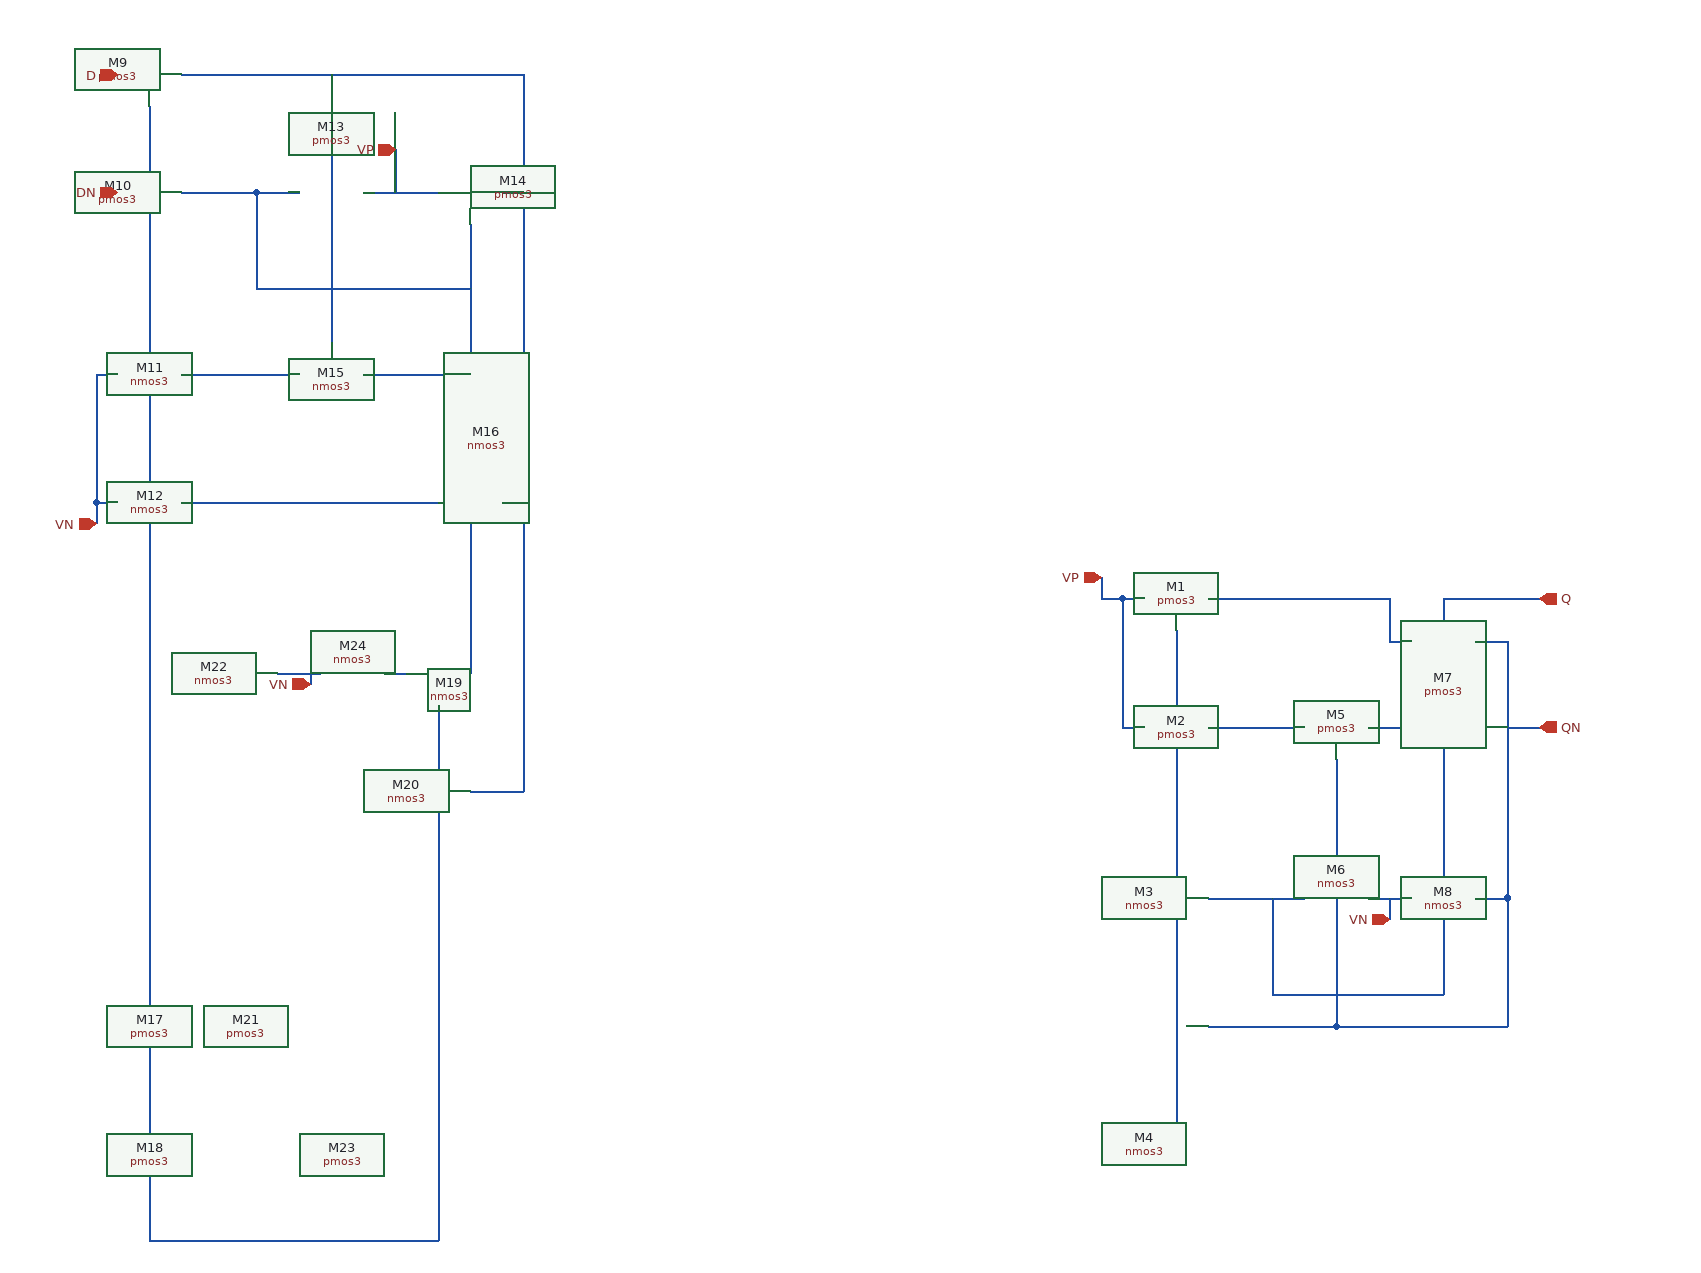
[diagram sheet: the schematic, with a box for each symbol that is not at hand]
v {xschem version=2.9.9 file_version=1.2 }
G {}
K {}
V {}
S {}
E {}
N 1230 -280 1320 -280 { lab=#net1}
N 1230 -120 1320 -120 { lab=Q}
N 1230 0 1350 0 { lab=QN}
N 1350 -250 1350 0 { lab=QN}
N 1380 -280 1450 -280 { lab=Q}
N 1450 -280 1450 -90 { lab=Q}
N 1380 -120 1420 -120 { lab=VN}
N 1480 -120 1510 -120 { lab=QN}
N 1150 -280 1170 -280 { lab=VP}
N 1150 -400 1150 -280 { lab=VP}
N 1150 -400 1170 -400 { lab=VP}
N 1350 0 1510 0 { lab=QN}
N 1510 -120 1510 0 { lab=QN}
N 1290 -120 1290 -60 { lab=Q}
N 1290 -30 1450 -30 { lab=Q}
N 1450 -90 1450 -60 { lab=Q}
N 270 -890 500 -890 { lab=#net2}
N 270 -780 340 -780 { lab=#net3}
N 270 -610 340 -610 { lab=#net4}
N 240 -860 240 -460 { lab=#net5}
N 240 -460 240 -400 { lab=#net5}
N 410 -890 410 -640 { lab=#net2}
N 440 -610 540 -610 { lab=#net3}
N 270 -490 470 -490 { lab=#net6}
N 190 -610 210 -610 { lab=VN}
N 190 -610 190 -490 { lab=VN}
N 190 -490 210 -490 { lab=VN}
N 340 -780 340 -690 { lab=#net3}
N 340 -690 540 -690 { lab=#net3}
N 540 -750 540 -520 { lab=#net3}
N 570 -490 590 -490 { lab=#net2}
N 590 -890 590 -490 { lab=#net2}
N 540 -890 590 -890 { lab=#net2}
N 570 -780 590 -780 { lab=#net2}
N 440 -780 510 -780 { lab=VP}
N 470 -820 470 -780 { lab=VP}
N 1200 -370 1200 90 { lab=#net7}
N 190 -490 190 -470 { lab=VN}
N 1130 -420 1130 -400 { lab=VP}
N 1130 -400 1150 -400 { lab=VP}
N 1290 -60 1290 -30 { lab=Q}
N 1450 -60 1450 -30 { lab=Q}
N 1400 -120 1400 -100 { lab=VN}
N 1510 -280 1540 -280 { lab=QN}
N 1480 -360 1510 -360 { lab=QN}
N 1400 -360 1420 -360 { lab=#net8}
N 1400 -400 1400 -360 { lab=#net8}
N 1230 -400 1400 -400 { lab=#net8}
N 1510 -360 1510 -120 { lab=QN}
N 1450 -400 1450 -280 { lab=Q}
N 1450 -400 1540 -400 { lab=Q}
N 540 -520 540 -330 { lab=#net3}
N 240 30 240 200 { lab=#net5}
N 590 -490 590 -220 { lab=#net2}
N 540 -220 590 -220 { lab=#net2}
N 380 -330 400 -330 { lab=VN}
N 390 -330 390 -320 { lab=VN}
N 240 -400 240 30 { lab=#net5}
N 240 200 470 200 { lab=#net5}
N 510 -300 510 200 { lab=#net9}
N 460 -330 480 -330 { lab=#net10}
N 500 -890 540 -890 { lab=#net2}
N 340 -780 380 -780 { lab=#net3}
N 340 -610 380 -610 { lab=#net4}
N 470 -490 510 -490 {}
N 360 -330 380 -330 {}
N 470 200 510 200 {}
C {madvlsi/pmos3.sym} 1200 -400 3 0 {name=M1
L=0.15
W=1
body=VDD
nf=1
mult=1
ad="'int((nf+1)/2) * W/nf * 0.29'" 
pd="'2*int((nf+1)/2) * (W/nf + 0.29)'"
as="'int((nf+2)/2) * W/nf * 0.29'" 
ps="'2*int((nf+2)/2) * (W/nf + 0.29)'"
nrd="'0.29 / W'" nrs="'0.29 / W'"
sa=0 sb=0 sd=0
model=pfet_01v8
spiceprefix=X
}
C {madvlsi/pmos3.sym} 1200 -280 3 0 {name=M2
L=0.15
W=1
body=VDD
nf=1
mult=1
ad="'int((nf+1)/2) * W/nf * 0.29'" 
pd="'2*int((nf+1)/2) * (W/nf + 0.29)'"
as="'int((nf+2)/2) * W/nf * 0.29'" 
ps="'2*int((nf+2)/2) * (W/nf + 0.29)'"
nrd="'0.29 / W'" nrs="'0.29 / W'"
sa=0 sb=0 sd=0
model=pfet_01v8
spiceprefix=X
}
C {madvlsi/nmos3.sym} 1200 -120 3 0 {name=M3
L=0.15
W=1
body=GND
nf=1
mult=1
ad="'int((nf+1)/2) * W/nf * 0.29'" 
pd="'2*int((nf+1)/2) * (W/nf + 0.29)'"
as="'int((nf+2)/2) * W/nf * 0.29'" 
ps="'2*int((nf+2)/2) * (W/nf + 0.29)'"
nrd="'0.29 / W'" nrs="'0.29 / W'"
sa=0 sb=0 sd=0
model=nfet_01v8
spiceprefix=X
}
C {madvlsi/nmos3.sym} 1200 0 3 0 {name=M4
L=0.15
W=1
body=GND
nf=1
mult=1
ad="'int((nf+1)/2) * W/nf * 0.29'" 
pd="'2*int((nf+1)/2) * (W/nf + 0.29)'"
as="'int((nf+2)/2) * W/nf * 0.29'" 
ps="'2*int((nf+2)/2) * (W/nf + 0.29)'"
nrd="'0.29 / W'" nrs="'0.29 / W'"
sa=0 sb=0 sd=0
model=nfet_01v8
spiceprefix=X
}
C {madvlsi/pmos3.sym} 1350 -280 3 0 {name=M5
L=0.15
W=1
body=VDD
nf=1
mult=1
ad="'int((nf+1)/2) * W/nf * 0.29'" 
pd="'2*int((nf+1)/2) * (W/nf + 0.29)'"
as="'int((nf+2)/2) * W/nf * 0.29'" 
ps="'2*int((nf+2)/2) * (W/nf + 0.29)'"
nrd="'0.29 / W'" nrs="'0.29 / W'"
sa=0 sb=0 sd=0
model=pfet_01v8
spiceprefix=X
}
C {madvlsi/nmos3.sym} 1350 -120 3 0 {name=M6
L=0.15
W=1
body=GND
nf=1
mult=1
ad="'int((nf+1)/2) * W/nf * 0.29'" 
pd="'2*int((nf+1)/2) * (W/nf + 0.29)'"
as="'int((nf+2)/2) * W/nf * 0.29'" 
ps="'2*int((nf+2)/2) * (W/nf + 0.29)'"
nrd="'0.29 / W'" nrs="'0.29 / W'"
sa=0 sb=0 sd=0
model=nfet_01v8
spiceprefix=X
}
C {madvlsi/pmos3.sym} 1450 -360 3 0 {name=M7
L=0.15
W=1
body=VDD
nf=1
mult=1
ad="'int((nf+1)/2) * W/nf * 0.29'" 
pd="'2*int((nf+1)/2) * (W/nf + 0.29)'"
as="'int((nf+2)/2) * W/nf * 0.29'" 
ps="'2*int((nf+2)/2) * (W/nf + 0.29)'"
nrd="'0.29 / W'" nrs="'0.29 / W'"
sa=0 sb=0 sd=0
model=pfet_01v8
spiceprefix=X
}
C {madvlsi/nmos3.sym} 1450 -120 3 0 {name=M8
L=0.15
W=1
body=GND
nf=1
mult=1
ad="'int((nf+1)/2) * W/nf * 0.29'" 
pd="'2*int((nf+1)/2) * (W/nf + 0.29)'"
as="'int((nf+2)/2) * W/nf * 0.29'" 
ps="'2*int((nf+2)/2) * (W/nf + 0.29)'"
nrd="'0.29 / W'" nrs="'0.29 / W'"
sa=0 sb=0 sd=0
model=nfet_01v8
spiceprefix=X
}
C {madvlsi/pmos3.sym} 240 -890 3 0 {name=M9
L=0.15
W=1
body=VDD
nf=1
mult=1
ad="'int((nf+1)/2) * W/nf * 0.29'" 
pd="'2*int((nf+1)/2) * (W/nf + 0.29)'"
as="'int((nf+2)/2) * W/nf * 0.29'" 
ps="'2*int((nf+2)/2) * (W/nf + 0.29)'"
nrd="'0.29 / W'" nrs="'0.29 / W'"
sa=0 sb=0 sd=0
model=pfet_01v8
spiceprefix=X
}
C {madvlsi/pmos3.sym} 240 -780 3 0 {name=M10
L=0.15
W=1
body=VDD
nf=1
mult=1
ad="'int((nf+1)/2) * W/nf * 0.29'" 
pd="'2*int((nf+1)/2) * (W/nf + 0.29)'"
as="'int((nf+2)/2) * W/nf * 0.29'" 
ps="'2*int((nf+2)/2) * (W/nf + 0.29)'"
nrd="'0.29 / W'" nrs="'0.29 / W'"
sa=0 sb=0 sd=0
model=pfet_01v8
spiceprefix=X
}
C {madvlsi/nmos3.sym} 240 -610 3 0 {name=M11
L=0.15
W=1
body=GND
nf=1
mult=1
ad="'int((nf+1)/2) * W/nf * 0.29'" 
pd="'2*int((nf+1)/2) * (W/nf + 0.29)'"
as="'int((nf+2)/2) * W/nf * 0.29'" 
ps="'2*int((nf+2)/2) * (W/nf + 0.29)'"
nrd="'0.29 / W'" nrs="'0.29 / W'"
sa=0 sb=0 sd=0
model=nfet_01v8
spiceprefix=X
}
C {madvlsi/nmos3.sym} 240 -490 3 0 {name=M12
L=0.15
W=1
body=GND
nf=1
mult=1
ad="'int((nf+1)/2) * W/nf * 0.29'" 
pd="'2*int((nf+1)/2) * (W/nf + 0.29)'"
as="'int((nf+2)/2) * W/nf * 0.29'" 
ps="'2*int((nf+2)/2) * (W/nf + 0.29)'"
nrd="'0.29 / W'" nrs="'0.29 / W'"
sa=0 sb=0 sd=0
model=nfet_01v8
spiceprefix=X
}
C {madvlsi/pmos3.sym} 410 -780 3 0 {name=M13
L=0.15
W=1
body=VDD
nf=1
mult=1
ad="'int((nf+1)/2) * W/nf * 0.29'" 
pd="'2*int((nf+1)/2) * (W/nf + 0.29)'"
as="'int((nf+2)/2) * W/nf * 0.29'" 
ps="'2*int((nf+2)/2) * (W/nf + 0.29)'"
nrd="'0.29 / W'" nrs="'0.29 / W'"
sa=0 sb=0 sd=0
model=pfet_01v8
spiceprefix=X
}
C {madvlsi/pmos3.sym} 540 -780 3 0 {name=M14
L=0.15
W=1
body=VDD
nf=1
mult=1
ad="'int((nf+1)/2) * W/nf * 0.29'" 
pd="'2*int((nf+1)/2) * (W/nf + 0.29)'"
as="'int((nf+2)/2) * W/nf * 0.29'" 
ps="'2*int((nf+2)/2) * (W/nf + 0.29)'"
nrd="'0.29 / W'" nrs="'0.29 / W'"
sa=0 sb=0 sd=0
model=pfet_01v8
spiceprefix=X
}
C {madvlsi/nmos3.sym} 410 -610 1 0 {name=M15
L=0.15
W=1
body=GND
nf=1
mult=1
ad="'int((nf+1)/2) * W/nf * 0.29'" 
pd="'2*int((nf+1)/2) * (W/nf + 0.29)'"
as="'int((nf+2)/2) * W/nf * 0.29'" 
ps="'2*int((nf+2)/2) * (W/nf + 0.29)'"
nrd="'0.29 / W'" nrs="'0.29 / W'"
sa=0 sb=0 sd=0
model=nfet_01v8
spiceprefix=X
}
C {madvlsi/nmos3.sym} 540 -490 1 0 {name=M16
L=0.15
W=1
body=GND
nf=1
mult=1
ad="'int((nf+1)/2) * W/nf * 0.29'" 
pd="'2*int((nf+1)/2) * (W/nf + 0.29)'"
as="'int((nf+2)/2) * W/nf * 0.29'" 
ps="'2*int((nf+2)/2) * (W/nf + 0.29)'"
nrd="'0.29 / W'" nrs="'0.29 / W'"
sa=0 sb=0 sd=0
model=nfet_01v8
spiceprefix=X
}
C {devices/iopin.sym} 1130 -420 3 0 {name=p1 lab=VP}
C {devices/iopin.sym} 470 -820 3 0 {name=p2 lab=VP}
C {devices/iopin.sym} 190 -470 1 0 {name=p3 lab=VN}
C {devices/iopin.sym} 1400 -100 1 0 {name=p4 lab=VN}
C {devices/ipin.sym} 210 -890 0 0 {name=p5 lab=D}
C {devices/ipin.sym} 210 -780 0 0 {name=p6 lab=DN}
C {devices/opin.sym} 1540 -280 0 0 {name=p8 lab=QN}
C {devices/opin.sym} 1540 -400 0 0 {name=p9 lab=Q}
C {madvlsi/pmos3.sym} 240 0 3 0 {name=M17
L=0.15
W=1
body=VDD
nf=1
mult=1
ad="'int((nf+1)/2) * W/nf * 0.29'" 
pd="'2*int((nf+1)/2) * (W/nf + 0.29)'"
as="'int((nf+2)/2) * W/nf * 0.29'" 
ps="'2*int((nf+2)/2) * (W/nf + 0.29)'"
nrd="'0.29 / W'" nrs="'0.29 / W'"
sa=0 sb=0 sd=0
model=pfet_01v8
spiceprefix=X
}
C {madvlsi/pmos3.sym} 240 120 3 0 {name=M18
L=0.15
W=1
body=VDD
nf=1
mult=1
ad="'int((nf+1)/2) * W/nf * 0.29'" 
pd="'2*int((nf+1)/2) * (W/nf + 0.29)'"
as="'int((nf+2)/2) * W/nf * 0.29'" 
ps="'2*int((nf+2)/2) * (W/nf + 0.29)'"
nrd="'0.29 / W'" nrs="'0.29 / W'"
sa=0 sb=0 sd=0
model=pfet_01v8
spiceprefix=X
}
C {madvlsi/nmos3.sym} 510 -330 3 0 {name=M19
L=0.15
W=1
body=GND
nf=1
mult=1
ad="'int((nf+1)/2) * W/nf * 0.29'" 
pd="'2*int((nf+1)/2) * (W/nf + 0.29)'"
as="'int((nf+2)/2) * W/nf * 0.29'" 
ps="'2*int((nf+2)/2) * (W/nf + 0.29)'"
nrd="'0.29 / W'" nrs="'0.29 / W'"
sa=0 sb=0 sd=0
model=nfet_01v8
spiceprefix=X
}
C {madvlsi/nmos3.sym} 510 -220 3 0 {name=M20
L=0.15
W=1
body=GND
nf=1
mult=1
ad="'int((nf+1)/2) * W/nf * 0.29'" 
pd="'2*int((nf+1)/2) * (W/nf + 0.29)'"
as="'int((nf+2)/2) * W/nf * 0.29'" 
ps="'2*int((nf+2)/2) * (W/nf + 0.29)'"
nrd="'0.29 / W'" nrs="'0.29 / W'"
sa=0 sb=0 sd=0
model=nfet_01v8
spiceprefix=X
}
C {madvlsi/pmos3.sym} 330 0 3 0 {name=M21
L=0.15
W=1
body=VDD
nf=1
mult=1
ad="'int((nf+1)/2) * W/nf * 0.29'" 
pd="'2*int((nf+1)/2) * (W/nf + 0.29)'"
as="'int((nf+2)/2) * W/nf * 0.29'" 
ps="'2*int((nf+2)/2) * (W/nf + 0.29)'"
nrd="'0.29 / W'" nrs="'0.29 / W'"
sa=0 sb=0 sd=0
model=pfet_01v8
spiceprefix=X
}
C {madvlsi/nmos3.sym} 330 -330 3 0 {name=M22
L=0.15
W=1
body=GND
nf=1
mult=1
ad="'int((nf+1)/2) * W/nf * 0.29'" 
pd="'2*int((nf+1)/2) * (W/nf + 0.29)'"
as="'int((nf+2)/2) * W/nf * 0.29'" 
ps="'2*int((nf+2)/2) * (W/nf + 0.29)'"
nrd="'0.29 / W'" nrs="'0.29 / W'"
sa=0 sb=0 sd=0
model=nfet_01v8
spiceprefix=X
}
C {madvlsi/pmos3.sym} 420 120 3 0 {name=M23
L=0.15
W=1
body=VDD
nf=1
mult=1
ad="'int((nf+1)/2) * W/nf * 0.29'" 
pd="'2*int((nf+1)/2) * (W/nf + 0.29)'"
as="'int((nf+2)/2) * W/nf * 0.29'" 
ps="'2*int((nf+2)/2) * (W/nf + 0.29)'"
nrd="'0.29 / W'" nrs="'0.29 / W'"
sa=0 sb=0 sd=0
model=pfet_01v8
spiceprefix=X
}
C {madvlsi/nmos3.sym} 430 -330 3 0 {name=M24
L=0.15
W=1
body=GND
nf=1
mult=1
ad="'int((nf+1)/2) * W/nf * 0.29'" 
pd="'2*int((nf+1)/2) * (W/nf + 0.29)'"
as="'int((nf+2)/2) * W/nf * 0.29'" 
ps="'2*int((nf+2)/2) * (W/nf + 0.29)'"
nrd="'0.29 / W'" nrs="'0.29 / W'"
sa=0 sb=0 sd=0
model=nfet_01v8
spiceprefix=X
}
C {devices/iopin.sym} 390 -320 1 0 {name=p7 lab=VN}
